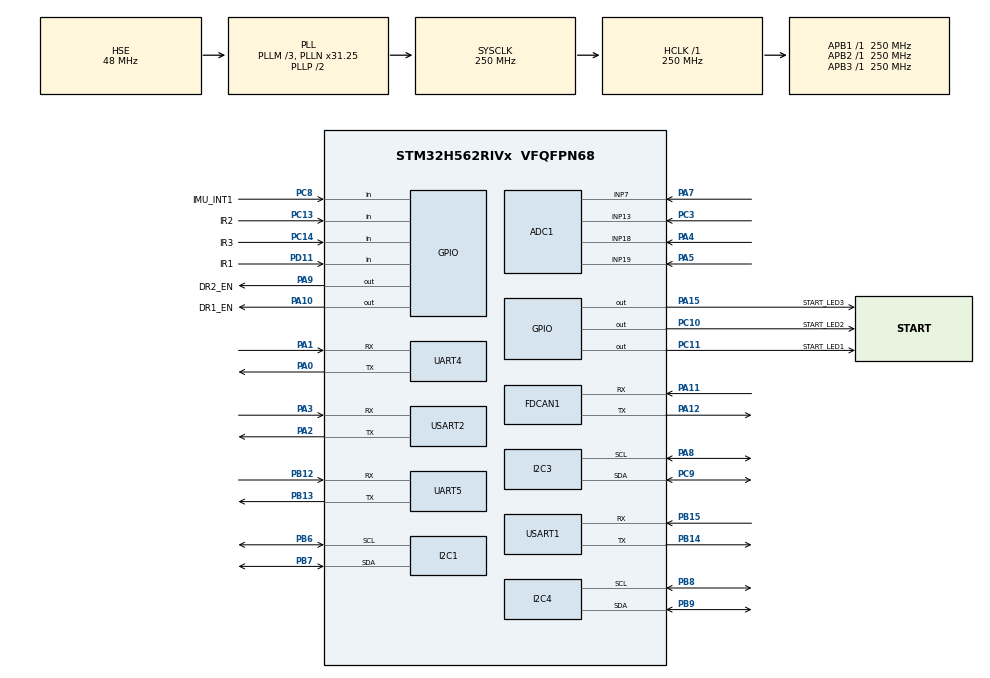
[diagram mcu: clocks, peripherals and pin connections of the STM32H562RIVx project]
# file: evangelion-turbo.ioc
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ADC1.Channel-7\#ChannelRegularConversion=ADC_CHANNEL_19
ADC1.MonitoredBy-7\#ChannelRegularConversion=__NULL
ADC1.NbrOfConversionFlag=1
ADC1.OffsetNumber-7\#ChannelRegularConversion=ADC_OFFSET_NONE
ADC1.Rank-7\#ChannelRegularConversion=1
ADC1.SamplingTime-7\#ChannelRegularConversion=ADC_SAMPLETIME_2CYCLES_5
ADC1.master=1
BOOTPATH.BootPathName=LEGACY
BOOTPATH.UserSelectedBootPath=LEGACY
CORTEX_M33_NS.userName=CORTEX_M33
FDCAN1.CalculateBaudRateNominal=1000000
FDCAN1.CalculateTimeBitNominal=1000
FDCAN1.CalculateTimeQuantumNominal=333.3333333333333
I2C1.Timing=0x60808CD3
I2C3.Timing=0x60808CD3
I2C4.Timing=0x60808CD3
Mcu.Family=STM32H5
Mcu.Name=STM32H562RIVx
Mcu.Package=VFQFPN68
NVIC.PriorityGroup=NVIC_PRIORITYGROUP_4
PA0.Mode=Asynchronous
PA0.Signal=UART4_TX
PA1.Mode=Asynchronous
PA1.Signal=UART4_RX
PA10.GPIO_Label=DR1_EN
PA10.Signal=GPIO_Output
PA11.Mode=FDCAN_Activate
PA11.Signal=FDCAN1_RX
PA12.Mode=FDCAN_Activate
PA12.Signal=FDCAN1_TX
PA13(JTMS/SWDIO).Mode=Serial_Wire
PA13(JTMS/SWDIO).Signal=DEBUG_JTMS-SWDIO
PA14(JTCK/SWCLK).Mode=Serial_Wire
PA14(JTCK/SWCLK).Signal=DEBUG_JTCK-SWCLK
PA15(JTDI).GPIO_Label=START_LED3
PA15(JTDI).Signal=GPIO_Output
PA2.Mode=Asynchronous
PA2.Signal=USART2_TX
PA3.Mode=Asynchronous
PA3.Signal=USART2_RX
PA4.Signal=ADCx_INP18
PA5.Signal=ADCx_INP19
PA6.Signal=ADCx_INP3
PA7.Signal=ADCx_INP7
PA8.Mode=I2C
PA8.Signal=I2C3_SCL
PA9.GPIO_Label=DR2_EN
PA9.Signal=GPIO_Output
PB1.Signal=ADCx_INP5
PB12.Mode=Asynchronous
PB12.Signal=UART5_RX
PB13.Mode=Asynchronous
PB13.Signal=UART5_TX
PB14.Mode=Asynchronous
PB14.Signal=USART1_TX
PB15.Mode=Asynchronous
PB15.Signal=USART1_RX
PB6.Mode=I2C
PB6.Signal=I2C1_SCL
PB7.Mode=I2C
PB7.Signal=I2C1_SDA
PB8.Mode=I2C
PB8.Signal=I2C4_SCL
PB9.Mode=I2C
PB9.Signal=I2C4_SDA
PC0.Signal=ADCx_INP10
PC1.Signal=ADCx_INP11
PC10.GPIO_Label=START_LED2
PC10.Signal=GPIO_Output
PC11.GPIO_Label=START_LED1
PC11.Signal=GPIO_Output
PC13.GPIO_Label=IR2
PC13.Signal=GPIO_Input
PC14-OSC32_IN(OSC32_IN).GPIO_Label=IR3
PC14-OSC32_IN(OSC32_IN).Signal=GPIO_Input
PC2.Signal=ADCx_INP12
PC3.Signal=ADCx_INP13
PC4.Signal=ADCx_INP4
PC6.Signal=S_TIM3_CH1
PC7.Signal=S_TIM3_CH2
PC8.GPIO_Label=IMU_INT1
PC8.Signal=GPIO_Input
PC9.Mode=I2C
PC9.Signal=I2C3_SDA
PD11.GPIO_Label=IR1
PD11.Signal=GPIO_Input
PH0-OSC_IN(PH0).Mode=HSE-External-Oscillator
PH0-OSC_IN(PH0).Signal=RCC_OSC_IN
PH1-OSC_OUT(PH1).Mode=HSE-External-Oscillator
PH1-OSC_OUT(PH1).Signal=RCC_OSC_OUT
ProjectManager.HeapSize=0x200
ProjectManager.StackSize=0x400
ProjectManager.TargetToolchain=STM32CubeIDE
RCC.ADCFreq_Value=250000000
RCC.AHBFreq_Value=250000000
RCC.APB1Freq_Value=250000000
RCC.APB1TimFreq_Value=250000000
RCC.APB2Freq_Value=250000000
RCC.APB2TimFreq_Value=250000000
RCC.APB3Freq_Value=250000000
RCC.CSI_VALUE=4000000
RCC.CortexFreq_Value=250000000
RCC.EPOD_VALUE=48000000
RCC.EnbaleCSS=true
RCC.HCLKFreq_Value=250000000
RCC.HSE_VALUE=48000000
RCC.HSI48_VALUE=48000000
RCC.HSI_VALUE=64000000
RCC.LSE_VALUE=32768
RCC.LSIRC_VALUE=32000
RCC.PLL2FRACN=0
RCC.PLL2Source=RCC_PLL2_SOURCE_HSE
RCC.PLL3FRACN=0
RCC.PLL3Source=RCC_PLL3_SOURCE_HSE
RCC.PLLFRACN=2048
RCC.PLLM=3
RCC.PLLN=31
RCC.PLLSourceVirtual=RCC_PLL1_SOURCE_HSE
RCC.SYSCLKFreq_VALUE=250000000
RCC.SYSCLKSource=RCC_SYSCLKSOURCE_PLLCLK
RCC.USBFreq_Value=48000000
RCC.VCOOutputFreq_Value=500000000
SH.ADCx_INP10.0=ADC1_INP10
SH.ADCx_INP11.0=ADC1_INP11
SH.ADCx_INP12.0=ADC1_INP12
SH.ADCx_INP13.0=ADC1_INP13,IN13-Single-Ended
SH.ADCx_INP18.0=ADC1_INP18,IN18-Single-Ended
SH.ADCx_INP19.0=ADC1_INP19,IN19-Single-Ended
SH.ADCx_INP3.0=ADC1_INP3
SH.ADCx_INP4.0=ADC1_INP4
SH.ADCx_INP5.0=ADC1_INP5
SH.ADCx_INP7.0=ADC1_INP7,IN7-Single-Ended
SH.S_TIM3_CH1.0=TIM3_CH1
SH.S_TIM3_CH2.0=TIM3_CH2
USART1.VirtualMode-Asynchronous=VM_ASYNC
USART2.VirtualMode-Asynchronous=VM_ASYNC
VP_BOOTPATH_VS_BOOTPATH.Mode=BP_Activate
VP_CORTEX_M33_NS_VS_Hclk.Mode=Hclk_Mode
VP_LPTIM1_VS_CH1.Mode=Channel_1_Active
VP_LPTIM1_VS_LPTIM_counterModeInternalClock.Mode=Counts__internal_clock_event_00
VP_LPTIM1_VS_noIO1.Mode=NoIO_Channel_1_Active
VP_MEMORYMAP_VS_MEMORYMAP.Mode=CurAppReg
VP_PWR_VS_LPOM.Mode=PowerOptimisation
VP_PWR_VS_SECSignals.Mode=Security/Privilege
board=custom

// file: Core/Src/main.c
/* USER CODE BEGIN Header */
/**
  ******************************************************************************
  * @file           : main.c
  * @brief          : Main program body
  ******************************************************************************
  * @attention
  *
  * Copyright (c) 2026 STMicroelectronics.
  * All rights reserved.
  *
  * This software is licensed under terms that can be found in the LICENSE file
  * in the root directory of this software component.
  * If no LICENSE file comes with this software, it is provided AS-IS.
  *
  ******************************************************************************
  */
/* USER CODE END Header */
#include "main.h"

ADC_HandleTypeDef hadc1;

FDCAN_HandleTypeDef hfdcan1;

I2C_HandleTypeDef hi2c1;
I2C_HandleTypeDef hi2c3;
I2C_HandleTypeDef hi2c4;

LPTIM_HandleTypeDef hlptim1;

UART_HandleTypeDef huart4;
UART_HandleTypeDef huart5;
UART_HandleTypeDef huart1;
UART_HandleTypeDef huart2;

void SystemClock_Config(void);
static void MX_GPIO_Init(void);
static void MX_ADC1_Init(void);
static void MX_I2C1_Init(void);
static void MX_I2C3_Init(void);
static void MX_I2C4_Init(void);
static void MX_LPTIM1_Init(void);
static void MX_UART4_Init(void);
static void MX_USART1_UART_Init(void);
static void MX_UART5_Init(void);
static void MX_FDCAN1_Init(void);
static void MX_USART2_UART_Init(void);

int main(void)
{

  /* MCU Configuration--------------------------------------------------------*/

  /* Reset of all peripherals, Initializes the Flash interface and the Systick. */
  HAL_Init();

  /* Configure the system clock */
  SystemClock_Config();

  /* Initialize all configured peripherals */
  MX_GPIO_Init();
  MX_ADC1_Init();
  MX_I2C1_Init();
  MX_I2C3_Init();
  MX_I2C4_Init();
  MX_LPTIM1_Init();
  MX_UART4_Init();
  MX_USART1_UART_Init();
  MX_UART5_Init();
  MX_FDCAN1_Init();
  MX_USART2_UART_Init();

  /* Infinite loop */
  while (1)
  {

  }
}

void SystemClock_Config(void)
{
  RCC_OscInitTypeDef RCC_OscInitStruct = {0};
  RCC_ClkInitTypeDef RCC_ClkInitStruct = {0};

  /** Configure the main internal regulator output voltage
  */
  __HAL_PWR_VOLTAGESCALING_CONFIG(PWR_REGULATOR_VOLTAGE_SCALE0);

  while(!__HAL_PWR_GET_FLAG(PWR_FLAG_VOSRDY)) {}

  /** Initializes the RCC Oscillators according to the specified parameters
  * in the RCC_OscInitTypeDef structure.
  */
  RCC_OscInitStruct.OscillatorType = RCC_OSCILLATORTYPE_HSE;
  RCC_OscInitStruct.HSEState = RCC_HSE_ON;
  RCC_OscInitStruct.PLL.PLLState = RCC_PLL_ON;
  RCC_OscInitStruct.PLL.PLLSource = RCC_PLL1_SOURCE_HSE;
  RCC_OscInitStruct.PLL.PLLM = 3;
  RCC_OscInitStruct.PLL.PLLN = 31;
  RCC_OscInitStruct.PLL.PLLP = 2;
  RCC_OscInitStruct.PLL.PLLQ = 2;
  RCC_OscInitStruct.PLL.PLLR = 2;
  RCC_OscInitStruct.PLL.PLLRGE = RCC_PLL1_VCIRANGE_3;
  RCC_OscInitStruct.PLL.PLLVCOSEL = RCC_PLL1_VCORANGE_WIDE;
  RCC_OscInitStruct.PLL.PLLFRACN = 2048;
  if (HAL_RCC_OscConfig(&RCC_OscInitStruct) != HAL_OK)
  {
    Error_Handler();
  }

  /** Initializes the CPU, AHB and APB buses clocks
  */
  RCC_ClkInitStruct.ClockType = RCC_CLOCKTYPE_HCLK|RCC_CLOCKTYPE_SYSCLK
                              |RCC_CLOCKTYPE_PCLK1|RCC_CLOCKTYPE_PCLK2
                              |RCC_CLOCKTYPE_PCLK3;
  RCC_ClkInitStruct.SYSCLKSource = RCC_SYSCLKSOURCE_PLLCLK;
  RCC_ClkInitStruct.AHBCLKDivider = RCC_SYSCLK_DIV1;
  RCC_ClkInitStruct.APB1CLKDivider = RCC_HCLK_DIV1;
  RCC_ClkInitStruct.APB2CLKDivider = RCC_HCLK_DIV1;
  RCC_ClkInitStruct.APB3CLKDivider = RCC_HCLK_DIV1;

  if (HAL_RCC_ClockConfig(&RCC_ClkInitStruct, FLASH_LATENCY_5) != HAL_OK)
  {
    Error_Handler();
  }

  /** Enables the Clock Security System
  */
  HAL_RCC_EnableCSS();

  /** Configure the programming delay
  */
  __HAL_FLASH_SET_PROGRAM_DELAY(FLASH_PROGRAMMING_DELAY_2);
}

static void MX_ADC1_Init(void)
{

  ADC_ChannelConfTypeDef sConfig = {0};

  /** Common config
  */
  hadc1.Instance = ADC1;
  hadc1.Init.ClockPrescaler = ADC_CLOCK_ASYNC_DIV4;
  hadc1.Init.Resolution = ADC_RESOLUTION_12B;
  hadc1.Init.DataAlign = ADC_DATAALIGN_RIGHT;
  hadc1.Init.ScanConvMode = ADC_SCAN_DISABLE;
  hadc1.Init.EOCSelection = ADC_EOC_SINGLE_CONV;
  hadc1.Init.LowPowerAutoWait = DISABLE;
  hadc1.Init.ContinuousConvMode = DISABLE;
  hadc1.Init.NbrOfConversion = 1;
  hadc1.Init.DiscontinuousConvMode = DISABLE;
  hadc1.Init.ExternalTrigConv = ADC_SOFTWARE_START;
  hadc1.Init.ExternalTrigConvEdge = ADC_EXTERNALTRIGCONVEDGE_NONE;
  hadc1.Init.DMAContinuousRequests = DISABLE;
  hadc1.Init.SamplingMode = ADC_SAMPLING_MODE_NORMAL;
  hadc1.Init.Overrun = ADC_OVR_DATA_PRESERVED;
  hadc1.Init.OversamplingMode = DISABLE;
  if (HAL_ADC_Init(&hadc1) != HAL_OK)
  {
    Error_Handler();
  }

  /** Configure Regular Channel
  */
  sConfig.Channel = ADC_CHANNEL_19;
  sConfig.Rank = ADC_REGULAR_RANK_1;
  sConfig.SamplingTime = ADC_SAMPLETIME_2CYCLES_5;
  sConfig.SingleDiff = ADC_SINGLE_ENDED;
  sConfig.OffsetNumber = ADC_OFFSET_NONE;
  sConfig.Offset = 0;
  if (HAL_ADC_ConfigChannel(&hadc1, &sConfig) != HAL_OK)
  {
    Error_Handler();
  }

}

static void MX_FDCAN1_Init(void)
{

  hfdcan1.Instance = FDCAN1;
  hfdcan1.Init.ClockDivider = FDCAN_CLOCK_DIV1;
  hfdcan1.Init.FrameFormat = FDCAN_FRAME_CLASSIC;
  hfdcan1.Init.Mode = FDCAN_MODE_NORMAL;
  hfdcan1.Init.AutoRetransmission = DISABLE;
  hfdcan1.Init.TransmitPause = DISABLE;
  hfdcan1.Init.ProtocolException = DISABLE;
  hfdcan1.Init.NominalPrescaler = 16;
  hfdcan1.Init.NominalSyncJumpWidth = 1;
  hfdcan1.Init.NominalTimeSeg1 = 1;
  hfdcan1.Init.NominalTimeSeg2 = 1;
  hfdcan1.Init.DataPrescaler = 1;
  hfdcan1.Init.DataSyncJumpWidth = 1;
  hfdcan1.Init.DataTimeSeg1 = 1;
  hfdcan1.Init.DataTimeSeg2 = 1;
  hfdcan1.Init.StdFiltersNbr = 0;
  hfdcan1.Init.ExtFiltersNbr = 0;
  hfdcan1.Init.TxFifoQueueMode = FDCAN_TX_FIFO_OPERATION;
  if (HAL_FDCAN_Init(&hfdcan1) != HAL_OK)
  {
    Error_Handler();
  }

}

static void MX_I2C1_Init(void)
{

  hi2c1.Instance = I2C1;
  hi2c1.Init.Timing = 0x60808CD3;
  hi2c1.Init.OwnAddress1 = 0;
  hi2c1.Init.AddressingMode = I2C_ADDRESSINGMODE_7BIT;
  hi2c1.Init.DualAddressMode = I2C_DUALADDRESS_DISABLE;
  hi2c1.Init.OwnAddress2 = 0;
  hi2c1.Init.OwnAddress2Masks = I2C_OA2_NOMASK;
  hi2c1.Init.GeneralCallMode = I2C_GENERALCALL_DISABLE;
  hi2c1.Init.NoStretchMode = I2C_NOSTRETCH_DISABLE;
  if (HAL_I2C_Init(&hi2c1) != HAL_OK)
  {
    Error_Handler();
  }

  /** Configure Analogue filter
  */
  if (HAL_I2CEx_ConfigAnalogFilter(&hi2c1, I2C_ANALOGFILTER_ENABLE) != HAL_OK)
  {
    Error_Handler();
  }

  /** Configure Digital filter
  */
  if (HAL_I2CEx_ConfigDigitalFilter(&hi2c1, 0) != HAL_OK)
  {
    Error_Handler();
  }

}

static void MX_I2C3_Init(void)
{

  hi2c3.Instance = I2C3;
  hi2c3.Init.Timing = 0x60808CD3;
  hi2c3.Init.OwnAddress1 = 0;
  hi2c3.Init.AddressingMode = I2C_ADDRESSINGMODE_7BIT;
  hi2c3.Init.DualAddressMode = I2C_DUALADDRESS_DISABLE;
  hi2c3.Init.OwnAddress2 = 0;
  hi2c3.Init.OwnAddress2Masks = I2C_OA2_NOMASK;
  hi2c3.Init.GeneralCallMode = I2C_GENERALCALL_DISABLE;
  hi2c3.Init.NoStretchMode = I2C_NOSTRETCH_DISABLE;
  if (HAL_I2C_Init(&hi2c3) != HAL_OK)
  {
    Error_Handler();
  }

  /** Configure Analogue filter
  */
  if (HAL_I2CEx_ConfigAnalogFilter(&hi2c3, I2C_ANALOGFILTER_ENABLE) != HAL_OK)
  {
    Error_Handler();
  }

  /** Configure Digital filter
  */
  if (HAL_I2CEx_ConfigDigitalFilter(&hi2c3, 0) != HAL_OK)
  {
    Error_Handler();
  }

}

static void MX_I2C4_Init(void)
{

  hi2c4.Instance = I2C4;
  hi2c4.Init.Timing = 0x60808CD3;
  hi2c4.Init.OwnAddress1 = 0;
  hi2c4.Init.AddressingMode = I2C_ADDRESSINGMODE_7BIT;
  hi2c4.Init.DualAddressMode = I2C_DUALADDRESS_DISABLE;
  hi2c4.Init.OwnAddress2 = 0;
  hi2c4.Init.OwnAddress2Masks = I2C_OA2_NOMASK;
  hi2c4.Init.GeneralCallMode = I2C_GENERALCALL_DISABLE;
  hi2c4.Init.NoStretchMode = I2C_NOSTRETCH_DISABLE;
  if (HAL_I2C_Init(&hi2c4) != HAL_OK)
  {
    Error_Handler();
  }

  /** Configure Analogue filter
  */
  if (HAL_I2CEx_ConfigAnalogFilter(&hi2c4, I2C_ANALOGFILTER_ENABLE) != HAL_OK)
  {
    Error_Handler();
  }

  /** Configure Digital filter
  */
  if (HAL_I2CEx_ConfigDigitalFilter(&hi2c4, 0) != HAL_OK)
  {
    Error_Handler();
  }

}

static void MX_LPTIM1_Init(void)
{

  LPTIM_OC_ConfigTypeDef sConfig1 = {0};

  hlptim1.Instance = LPTIM1;
  hlptim1.Init.Clock.Source = LPTIM_CLOCKSOURCE_APBCLOCK_LPOSC;
  hlptim1.Init.Clock.Prescaler = LPTIM_PRESCALER_DIV1;
  hlptim1.Init.Trigger.Source = LPTIM_TRIGSOURCE_SOFTWARE;
  hlptim1.Init.Period = 65535;
  hlptim1.Init.UpdateMode = LPTIM_UPDATE_IMMEDIATE;
  hlptim1.Init.CounterSource = LPTIM_COUNTERSOURCE_INTERNAL;
  hlptim1.Init.Input1Source = LPTIM_INPUT1SOURCE_GPIO;
  hlptim1.Init.Input2Source = LPTIM_INPUT2SOURCE_GPIO;
  hlptim1.Init.RepetitionCounter = 0;
  if (HAL_LPTIM_Init(&hlptim1) != HAL_OK)
  {
    Error_Handler();
  }
  sConfig1.Pulse = 0;
  sConfig1.OCPolarity = LPTIM_OCPOLARITY_HIGH;
  if (HAL_LPTIM_OC_ConfigChannel(&hlptim1, &sConfig1, LPTIM_CHANNEL_1) != HAL_OK)
  {
    Error_Handler();
  }

}

static void MX_UART4_Init(void)
{

  huart4.Instance = UART4;
  huart4.Init.BaudRate = 115200;
  huart4.Init.WordLength = UART_WORDLENGTH_8B;
  huart4.Init.StopBits = UART_STOPBITS_1;
  huart4.Init.Parity = UART_PARITY_NONE;
  huart4.Init.Mode = UART_MODE_TX_RX;
  huart4.Init.HwFlowCtl = UART_HWCONTROL_NONE;
  huart4.Init.OverSampling = UART_OVERSAMPLING_16;
  huart4.Init.OneBitSampling = UART_ONE_BIT_SAMPLE_DISABLE;
  huart4.Init.ClockPrescaler = UART_PRESCALER_DIV1;
  huart4.AdvancedInit.AdvFeatureInit = UART_ADVFEATURE_NO_INIT;
  if (HAL_UART_Init(&huart4) != HAL_OK)
  {
    Error_Handler();
  }
  if (HAL_UARTEx_SetTxFifoThreshold(&huart4, UART_TXFIFO_THRESHOLD_1_8) != HAL_OK)
  {
    Error_Handler();
  }
  if (HAL_UARTEx_SetRxFifoThreshold(&huart4, UART_RXFIFO_THRESHOLD_1_8) != HAL_OK)
  {
    Error_Handler();
  }
  if (HAL_UARTEx_DisableFifoMode(&huart4) != HAL_OK)
  {
    Error_Handler();
  }

}

static void MX_UART5_Init(void)
{

  huart5.Instance = UART5;
  huart5.Init.BaudRate = 115200;
  huart5.Init.WordLength = UART_WORDLENGTH_8B;
  huart5.Init.StopBits = UART_STOPBITS_1;
  huart5.Init.Parity = UART_PARITY_NONE;
  huart5.Init.Mode = UART_MODE_TX_RX;
  huart5.Init.HwFlowCtl = UART_HWCONTROL_NONE;
  huart5.Init.OverSampling = UART_OVERSAMPLING_16;
  huart5.Init.OneBitSampling = UART_ONE_BIT_SAMPLE_DISABLE;
  huart5.Init.ClockPrescaler = UART_PRESCALER_DIV1;
  huart5.AdvancedInit.AdvFeatureInit = UART_ADVFEATURE_NO_INIT;
  if (HAL_UART_Init(&huart5) != HAL_OK)
  {
    Error_Handler();
  }
  if (HAL_UARTEx_SetTxFifoThreshold(&huart5, UART_TXFIFO_THRESHOLD_1_8) != HAL_OK)
  {
    Error_Handler();
  }
  if (HAL_UARTEx_SetRxFifoThreshold(&huart5, UART_RXFIFO_THRESHOLD_1_8) != HAL_OK)
  {
    Error_Handler();
  }
  if (HAL_UARTEx_DisableFifoMode(&huart5) != HAL_OK)
  {
    Error_Handler();
  }

}

static void MX_USART1_UART_Init(void)
{

  huart1.Instance = USART1;
  huart1.Init.BaudRate = 115200;
  huart1.Init.WordLength = UART_WORDLENGTH_8B;
  huart1.Init.StopBits = UART_STOPBITS_1;
  huart1.Init.Parity = UART_PARITY_NONE;
  huart1.Init.Mode = UART_MODE_TX_RX;
  huart1.Init.HwFlowCtl = UART_HWCONTROL_NONE;
  huart1.Init.OverSampling = UART_OVERSAMPLING_16;
  huart1.Init.OneBitSampling = UART_ONE_BIT_SAMPLE_DISABLE;
  huart1.Init.ClockPrescaler = UART_PRESCALER_DIV1;
  huart1.AdvancedInit.AdvFeatureInit = UART_ADVFEATURE_NO_INIT;
  if (HAL_UART_Init(&huart1) != HAL_OK)
  {
    Error_Handler();
  }
  if (HAL_UARTEx_SetTxFifoThreshold(&huart1, UART_TXFIFO_THRESHOLD_1_8) != HAL_OK)
  {
    Error_Handler();
  }
  if (HAL_UARTEx_SetRxFifoThreshold(&huart1, UART_RXFIFO_THRESHOLD_1_8) != HAL_OK)
  {
    Error_Handler();
  }
  if (HAL_UARTEx_DisableFifoMode(&huart1) != HAL_OK)
  {
    Error_Handler();
  }

}

static void MX_USART2_UART_Init(void)
{

  huart2.Instance = USART2;
  huart2.Init.BaudRate = 115200;
  huart2.Init.WordLength = UART_WORDLENGTH_8B;
  huart2.Init.StopBits = UART_STOPBITS_1;
  huart2.Init.Parity = UART_PARITY_NONE;
  huart2.Init.Mode = UART_MODE_TX_RX;
  huart2.Init.HwFlowCtl = UART_HWCONTROL_NONE;
  huart2.Init.OverSampling = UART_OVERSAMPLING_16;
  huart2.Init.OneBitSampling = UART_ONE_BIT_SAMPLE_DISABLE;
  huart2.Init.ClockPrescaler = UART_PRESCALER_DIV1;
  huart2.AdvancedInit.AdvFeatureInit = UART_ADVFEATURE_NO_INIT;
  if (HAL_UART_Init(&huart2) != HAL_OK)
  {
    Error_Handler();
  }
  if (HAL_UARTEx_SetTxFifoThreshold(&huart2, UART_TXFIFO_THRESHOLD_1_8) != HAL_OK)
  {
    Error_Handler();
  }
  if (HAL_UARTEx_SetRxFifoThreshold(&huart2, UART_RXFIFO_THRESHOLD_1_8) != HAL_OK)
  {
    Error_Handler();
  }
  if (HAL_UARTEx_DisableFifoMode(&huart2) != HAL_OK)
  {
    Error_Handler();
  }

}

static void MX_GPIO_Init(void)
{
  GPIO_InitTypeDef GPIO_InitStruct = {0};

  /* GPIO Ports Clock Enable */
  __HAL_RCC_GPIOC_CLK_ENABLE();
  __HAL_RCC_GPIOH_CLK_ENABLE();
  __HAL_RCC_GPIOA_CLK_ENABLE();
  __HAL_RCC_GPIOB_CLK_ENABLE();
  __HAL_RCC_GPIOD_CLK_ENABLE();

  /*Configure GPIO pin Output Level */
  HAL_GPIO_WritePin(GPIOA, DR2_EN_Pin|DR1_EN_Pin|START_LED3_Pin, GPIO_PIN_RESET);

  /*Configure GPIO pin Output Level */
  HAL_GPIO_WritePin(GPIOC, START_LED2_Pin|START_LED1_Pin, GPIO_PIN_RESET);

  /*Configure GPIO pins : IR2_Pin JOY1_Pin IMU_INT2_Pin IMU_INT1_Pin */
  GPIO_InitStruct.Pin = IR2_Pin|JOY1_Pin|IMU_INT2_Pin|IMU_INT1_Pin;
  GPIO_InitStruct.Mode = GPIO_MODE_INPUT;
  GPIO_InitStruct.Pull = GPIO_NOPULL;
  HAL_GPIO_Init(GPIOC, &GPIO_InitStruct);

  /*Configure GPIO pins : JOY2_Pin JOY3_Pin JOY4_Pin JOY5_Pin
                           PB5 */
  GPIO_InitStruct.Pin = JOY2_Pin|JOY3_Pin|JOY4_Pin|JOY5_Pin
                          |GPIO_PIN_5;
  GPIO_InitStruct.Mode = GPIO_MODE_INPUT;
  GPIO_InitStruct.Pull = GPIO_NOPULL;
  HAL_GPIO_Init(GPIOB, &GPIO_InitStruct);

  /*Configure GPIO pin : FAN_Pin */
  GPIO_InitStruct.Pin = FAN_Pin;
  GPIO_InitStruct.Mode = GPIO_MODE_AF_PP;
  GPIO_InitStruct.Pull = GPIO_NOPULL;
  GPIO_InitStruct.Speed = GPIO_SPEED_FREQ_LOW;
  GPIO_InitStruct.Alternate = GPIO_AF1_TIM2;
  HAL_GPIO_Init(FAN_GPIO_Port, &GPIO_InitStruct);

  /*Configure GPIO pin : IR1_Pin */
  GPIO_InitStruct.Pin = IR1_Pin;
  GPIO_InitStruct.Mode = GPIO_MODE_INPUT;
  GPIO_InitStruct.Pull = GPIO_NOPULL;
  HAL_GPIO_Init(IR1_GPIO_Port, &GPIO_InitStruct);

  /*Configure GPIO pins : DR2_EN_Pin DR1_EN_Pin START_LED3_Pin */
  GPIO_InitStruct.Pin = DR2_EN_Pin|DR1_EN_Pin|START_LED3_Pin;
  GPIO_InitStruct.Mode = GPIO_MODE_OUTPUT_PP;
  GPIO_InitStruct.Pull = GPIO_NOPULL;
  GPIO_InitStruct.Speed = GPIO_SPEED_FREQ_LOW;
  HAL_GPIO_Init(GPIOA, &GPIO_InitStruct);

  /*Configure GPIO pins : START_LED2_Pin START_LED1_Pin */
  GPIO_InitStruct.Pin = START_LED2_Pin|START_LED1_Pin;
  GPIO_InitStruct.Mode = GPIO_MODE_OUTPUT_PP;
  GPIO_InitStruct.Pull = GPIO_NOPULL;
  GPIO_InitStruct.Speed = GPIO_SPEED_FREQ_LOW;
  HAL_GPIO_Init(GPIOC, &GPIO_InitStruct);

}

void Error_Handler(void)
{
  __disable_irq();
  while (1)
  {
  }
}
